VERSION 5.7 ;
BUSBITCHARS "[]" ;
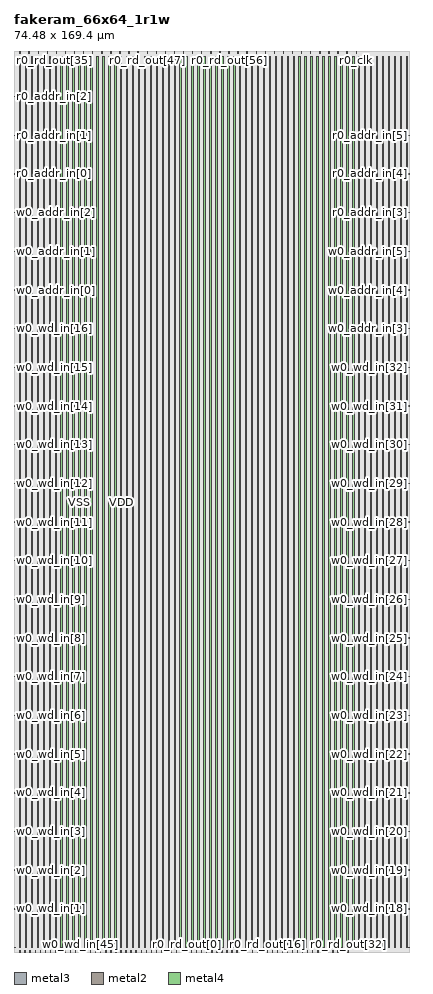
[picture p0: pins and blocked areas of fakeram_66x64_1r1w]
MACRO fakeram_66x64_1r1w
  FOREIGN fakeram_66x64_1r1w 0 0 ;
  SYMMETRY X Y R90 ;
  SIZE 74.480 BY 169.400 ;
  CLASS BLOCK ;
  PIN w0_wd_in[0]
    DIRECTION INPUT ;
    USE SIGNAL ;
    SHAPE ABUTMENT ;
    PORT
      LAYER metal3 ;
      RECT 0.000 0.805 0.210 0.875 ;
    END
  END w0_wd_in[0]
  PIN w0_wd_in[1]
    DIRECTION INPUT ;
    USE SIGNAL ;
    SHAPE ABUTMENT ;
    PORT
      LAYER metal3 ;
      RECT 0.000 8.085 0.210 8.155 ;
    END
  END w0_wd_in[1]
  PIN w0_wd_in[2]
    DIRECTION INPUT ;
    USE SIGNAL ;
    SHAPE ABUTMENT ;
    PORT
      LAYER metal3 ;
      RECT 0.000 15.365 0.210 15.435 ;
    END
  END w0_wd_in[2]
  PIN w0_wd_in[3]
    DIRECTION INPUT ;
    USE SIGNAL ;
    SHAPE ABUTMENT ;
    PORT
      LAYER metal3 ;
      RECT 0.000 22.645 0.210 22.715 ;
    END
  END w0_wd_in[3]
  PIN w0_wd_in[4]
    DIRECTION INPUT ;
    USE SIGNAL ;
    SHAPE ABUTMENT ;
    PORT
      LAYER metal3 ;
      RECT 0.000 29.925 0.210 29.995 ;
    END
  END w0_wd_in[4]
  PIN w0_wd_in[5]
    DIRECTION INPUT ;
    USE SIGNAL ;
    SHAPE ABUTMENT ;
    PORT
      LAYER metal3 ;
      RECT 0.000 37.205 0.210 37.275 ;
    END
  END w0_wd_in[5]
  PIN w0_wd_in[6]
    DIRECTION INPUT ;
    USE SIGNAL ;
    SHAPE ABUTMENT ;
    PORT
      LAYER metal3 ;
      RECT 0.000 44.485 0.210 44.555 ;
    END
  END w0_wd_in[6]
  PIN w0_wd_in[7]
    DIRECTION INPUT ;
    USE SIGNAL ;
    SHAPE ABUTMENT ;
    PORT
      LAYER metal3 ;
      RECT 0.000 51.765 0.210 51.835 ;
    END
  END w0_wd_in[7]
  PIN w0_wd_in[8]
    DIRECTION INPUT ;
    USE SIGNAL ;
    SHAPE ABUTMENT ;
    PORT
      LAYER metal3 ;
      RECT 0.000 59.045 0.210 59.115 ;
    END
  END w0_wd_in[8]
  PIN w0_wd_in[9]
    DIRECTION INPUT ;
    USE SIGNAL ;
    SHAPE ABUTMENT ;
    PORT
      LAYER metal3 ;
      RECT 0.000 66.325 0.210 66.395 ;
    END
  END w0_wd_in[9]
  PIN w0_wd_in[10]
    DIRECTION INPUT ;
    USE SIGNAL ;
    SHAPE ABUTMENT ;
    PORT
      LAYER metal3 ;
      RECT 0.000 73.605 0.210 73.675 ;
    END
  END w0_wd_in[10]
  PIN w0_wd_in[11]
    DIRECTION INPUT ;
    USE SIGNAL ;
    SHAPE ABUTMENT ;
    PORT
      LAYER metal3 ;
      RECT 0.000 80.885 0.210 80.955 ;
    END
  END w0_wd_in[11]
  PIN w0_wd_in[12]
    DIRECTION INPUT ;
    USE SIGNAL ;
    SHAPE ABUTMENT ;
    PORT
      LAYER metal3 ;
      RECT 0.000 88.165 0.210 88.235 ;
    END
  END w0_wd_in[12]
  PIN w0_wd_in[13]
    DIRECTION INPUT ;
    USE SIGNAL ;
    SHAPE ABUTMENT ;
    PORT
      LAYER metal3 ;
      RECT 0.000 95.445 0.210 95.515 ;
    END
  END w0_wd_in[13]
  PIN w0_wd_in[14]
    DIRECTION INPUT ;
    USE SIGNAL ;
    SHAPE ABUTMENT ;
    PORT
      LAYER metal3 ;
      RECT 0.000 102.725 0.210 102.795 ;
    END
  END w0_wd_in[14]
  PIN w0_wd_in[15]
    DIRECTION INPUT ;
    USE SIGNAL ;
    SHAPE ABUTMENT ;
    PORT
      LAYER metal3 ;
      RECT 0.000 110.005 0.210 110.075 ;
    END
  END w0_wd_in[15]
  PIN w0_wd_in[16]
    DIRECTION INPUT ;
    USE SIGNAL ;
    SHAPE ABUTMENT ;
    PORT
      LAYER metal3 ;
      RECT 0.000 117.285 0.210 117.355 ;
    END
  END w0_wd_in[16]
  PIN w0_wd_in[17]
    DIRECTION INPUT ;
    USE SIGNAL ;
    SHAPE ABUTMENT ;
    PORT
      LAYER metal3 ;
      RECT 74.270 0.805 74.480 0.875 ;
    END
  END w0_wd_in[17]
  PIN w0_wd_in[18]
    DIRECTION INPUT ;
    USE SIGNAL ;
    SHAPE ABUTMENT ;
    PORT
      LAYER metal3 ;
      RECT 74.270 8.085 74.480 8.155 ;
    END
  END w0_wd_in[18]
  PIN w0_wd_in[19]
    DIRECTION INPUT ;
    USE SIGNAL ;
    SHAPE ABUTMENT ;
    PORT
      LAYER metal3 ;
      RECT 74.270 15.365 74.480 15.435 ;
    END
  END w0_wd_in[19]
  PIN w0_wd_in[20]
    DIRECTION INPUT ;
    USE SIGNAL ;
    SHAPE ABUTMENT ;
    PORT
      LAYER metal3 ;
      RECT 74.270 22.645 74.480 22.715 ;
    END
  END w0_wd_in[20]
  PIN w0_wd_in[21]
    DIRECTION INPUT ;
    USE SIGNAL ;
    SHAPE ABUTMENT ;
    PORT
      LAYER metal3 ;
      RECT 74.270 29.925 74.480 29.995 ;
    END
  END w0_wd_in[21]
  PIN w0_wd_in[22]
    DIRECTION INPUT ;
    USE SIGNAL ;
    SHAPE ABUTMENT ;
    PORT
      LAYER metal3 ;
      RECT 74.270 37.205 74.480 37.275 ;
    END
  END w0_wd_in[22]
  PIN w0_wd_in[23]
    DIRECTION INPUT ;
    USE SIGNAL ;
    SHAPE ABUTMENT ;
    PORT
      LAYER metal3 ;
      RECT 74.270 44.485 74.480 44.555 ;
    END
  END w0_wd_in[23]
  PIN w0_wd_in[24]
    DIRECTION INPUT ;
    USE SIGNAL ;
    SHAPE ABUTMENT ;
    PORT
      LAYER metal3 ;
      RECT 74.270 51.765 74.480 51.835 ;
    END
  END w0_wd_in[24]
  PIN w0_wd_in[25]
    DIRECTION INPUT ;
    USE SIGNAL ;
    SHAPE ABUTMENT ;
    PORT
      LAYER metal3 ;
      RECT 74.270 59.045 74.480 59.115 ;
    END
  END w0_wd_in[25]
  PIN w0_wd_in[26]
    DIRECTION INPUT ;
    USE SIGNAL ;
    SHAPE ABUTMENT ;
    PORT
      LAYER metal3 ;
      RECT 74.270 66.325 74.480 66.395 ;
    END
  END w0_wd_in[26]
  PIN w0_wd_in[27]
    DIRECTION INPUT ;
    USE SIGNAL ;
    SHAPE ABUTMENT ;
    PORT
      LAYER metal3 ;
      RECT 74.270 73.605 74.480 73.675 ;
    END
  END w0_wd_in[27]
  PIN w0_wd_in[28]
    DIRECTION INPUT ;
    USE SIGNAL ;
    SHAPE ABUTMENT ;
    PORT
      LAYER metal3 ;
      RECT 74.270 80.885 74.480 80.955 ;
    END
  END w0_wd_in[28]
  PIN w0_wd_in[29]
    DIRECTION INPUT ;
    USE SIGNAL ;
    SHAPE ABUTMENT ;
    PORT
      LAYER metal3 ;
      RECT 74.270 88.165 74.480 88.235 ;
    END
  END w0_wd_in[29]
  PIN w0_wd_in[30]
    DIRECTION INPUT ;
    USE SIGNAL ;
    SHAPE ABUTMENT ;
    PORT
      LAYER metal3 ;
      RECT 74.270 95.445 74.480 95.515 ;
    END
  END w0_wd_in[30]
  PIN w0_wd_in[31]
    DIRECTION INPUT ;
    USE SIGNAL ;
    SHAPE ABUTMENT ;
    PORT
      LAYER metal3 ;
      RECT 74.270 102.725 74.480 102.795 ;
    END
  END w0_wd_in[31]
  PIN w0_wd_in[32]
    DIRECTION INPUT ;
    USE SIGNAL ;
    SHAPE ABUTMENT ;
    PORT
      LAYER metal3 ;
      RECT 74.270 110.005 74.480 110.075 ;
    END
  END w0_wd_in[32]
  PIN w0_wd_in[33]
    DIRECTION INPUT ;
    USE SIGNAL ;
    SHAPE ABUTMENT ;
    PORT
      LAYER metal2 ;
      RECT 1.105 0.000 1.175 0.210 ;
    END
  END w0_wd_in[33]
  PIN w0_wd_in[34]
    DIRECTION INPUT ;
    USE SIGNAL ;
    SHAPE ABUTMENT ;
    PORT
      LAYER metal2 ;
      RECT 2.055 0.000 2.125 0.210 ;
    END
  END w0_wd_in[34]
  PIN w0_wd_in[35]
    DIRECTION INPUT ;
    USE SIGNAL ;
    SHAPE ABUTMENT ;
    PORT
      LAYER metal2 ;
      RECT 3.005 0.000 3.075 0.210 ;
    END
  END w0_wd_in[35]
  PIN w0_wd_in[36]
    DIRECTION INPUT ;
    USE SIGNAL ;
    SHAPE ABUTMENT ;
    PORT
      LAYER metal2 ;
      RECT 3.955 0.000 4.025 0.210 ;
    END
  END w0_wd_in[36]
  PIN w0_wd_in[37]
    DIRECTION INPUT ;
    USE SIGNAL ;
    SHAPE ABUTMENT ;
    PORT
      LAYER metal2 ;
      RECT 4.905 0.000 4.975 0.210 ;
    END
  END w0_wd_in[37]
  PIN w0_wd_in[38]
    DIRECTION INPUT ;
    USE SIGNAL ;
    SHAPE ABUTMENT ;
    PORT
      LAYER metal2 ;
      RECT 5.855 0.000 5.925 0.210 ;
    END
  END w0_wd_in[38]
  PIN w0_wd_in[39]
    DIRECTION INPUT ;
    USE SIGNAL ;
    SHAPE ABUTMENT ;
    PORT
      LAYER metal2 ;
      RECT 6.805 0.000 6.875 0.210 ;
    END
  END w0_wd_in[39]
  PIN w0_wd_in[40]
    DIRECTION INPUT ;
    USE SIGNAL ;
    SHAPE ABUTMENT ;
    PORT
      LAYER metal2 ;
      RECT 7.755 0.000 7.825 0.210 ;
    END
  END w0_wd_in[40]
  PIN w0_wd_in[41]
    DIRECTION INPUT ;
    USE SIGNAL ;
    SHAPE ABUTMENT ;
    PORT
      LAYER metal2 ;
      RECT 8.705 0.000 8.775 0.210 ;
    END
  END w0_wd_in[41]
  PIN w0_wd_in[42]
    DIRECTION INPUT ;
    USE SIGNAL ;
    SHAPE ABUTMENT ;
    PORT
      LAYER metal2 ;
      RECT 9.655 0.000 9.725 0.210 ;
    END
  END w0_wd_in[42]
  PIN w0_wd_in[43]
    DIRECTION INPUT ;
    USE SIGNAL ;
    SHAPE ABUTMENT ;
    PORT
      LAYER metal2 ;
      RECT 10.605 0.000 10.675 0.210 ;
    END
  END w0_wd_in[43]
  PIN w0_wd_in[44]
    DIRECTION INPUT ;
    USE SIGNAL ;
    SHAPE ABUTMENT ;
    PORT
      LAYER metal2 ;
      RECT 11.555 0.000 11.625 0.210 ;
    END
  END w0_wd_in[44]
  PIN w0_wd_in[45]
    DIRECTION INPUT ;
    USE SIGNAL ;
    SHAPE ABUTMENT ;
    PORT
      LAYER metal2 ;
      RECT 12.505 0.000 12.575 0.210 ;
    END
  END w0_wd_in[45]
  PIN w0_wd_in[46]
    DIRECTION INPUT ;
    USE SIGNAL ;
    SHAPE ABUTMENT ;
    PORT
      LAYER metal2 ;
      RECT 13.455 0.000 13.525 0.210 ;
    END
  END w0_wd_in[46]
  PIN w0_wd_in[47]
    DIRECTION INPUT ;
    USE SIGNAL ;
    SHAPE ABUTMENT ;
    PORT
      LAYER metal2 ;
      RECT 14.405 0.000 14.475 0.210 ;
    END
  END w0_wd_in[47]
  PIN w0_wd_in[48]
    DIRECTION INPUT ;
    USE SIGNAL ;
    SHAPE ABUTMENT ;
    PORT
      LAYER metal2 ;
      RECT 15.355 0.000 15.425 0.210 ;
    END
  END w0_wd_in[48]
  PIN w0_wd_in[49]
    DIRECTION INPUT ;
    USE SIGNAL ;
    SHAPE ABUTMENT ;
    PORT
      LAYER metal2 ;
      RECT 16.305 0.000 16.375 0.210 ;
    END
  END w0_wd_in[49]
  PIN w0_wd_in[50]
    DIRECTION INPUT ;
    USE SIGNAL ;
    SHAPE ABUTMENT ;
    PORT
      LAYER metal2 ;
      RECT 17.255 0.000 17.325 0.210 ;
    END
  END w0_wd_in[50]
  PIN w0_wd_in[51]
    DIRECTION INPUT ;
    USE SIGNAL ;
    SHAPE ABUTMENT ;
    PORT
      LAYER metal2 ;
      RECT 18.205 0.000 18.275 0.210 ;
    END
  END w0_wd_in[51]
  PIN w0_wd_in[52]
    DIRECTION INPUT ;
    USE SIGNAL ;
    SHAPE ABUTMENT ;
    PORT
      LAYER metal2 ;
      RECT 19.155 0.000 19.225 0.210 ;
    END
  END w0_wd_in[52]
  PIN w0_wd_in[53]
    DIRECTION INPUT ;
    USE SIGNAL ;
    SHAPE ABUTMENT ;
    PORT
      LAYER metal2 ;
      RECT 20.105 0.000 20.175 0.210 ;
    END
  END w0_wd_in[53]
  PIN w0_wd_in[54]
    DIRECTION INPUT ;
    USE SIGNAL ;
    SHAPE ABUTMENT ;
    PORT
      LAYER metal2 ;
      RECT 21.055 0.000 21.125 0.210 ;
    END
  END w0_wd_in[54]
  PIN w0_wd_in[55]
    DIRECTION INPUT ;
    USE SIGNAL ;
    SHAPE ABUTMENT ;
    PORT
      LAYER metal2 ;
      RECT 22.005 0.000 22.075 0.210 ;
    END
  END w0_wd_in[55]
  PIN w0_wd_in[56]
    DIRECTION INPUT ;
    USE SIGNAL ;
    SHAPE ABUTMENT ;
    PORT
      LAYER metal2 ;
      RECT 22.955 0.000 23.025 0.210 ;
    END
  END w0_wd_in[56]
  PIN w0_wd_in[57]
    DIRECTION INPUT ;
    USE SIGNAL ;
    SHAPE ABUTMENT ;
    PORT
      LAYER metal2 ;
      RECT 23.905 0.000 23.975 0.210 ;
    END
  END w0_wd_in[57]
  PIN w0_wd_in[58]
    DIRECTION INPUT ;
    USE SIGNAL ;
    SHAPE ABUTMENT ;
    PORT
      LAYER metal2 ;
      RECT 24.855 0.000 24.925 0.210 ;
    END
  END w0_wd_in[58]
  PIN w0_wd_in[59]
    DIRECTION INPUT ;
    USE SIGNAL ;
    SHAPE ABUTMENT ;
    PORT
      LAYER metal2 ;
      RECT 25.805 0.000 25.875 0.210 ;
    END
  END w0_wd_in[59]
  PIN w0_wd_in[60]
    DIRECTION INPUT ;
    USE SIGNAL ;
    SHAPE ABUTMENT ;
    PORT
      LAYER metal2 ;
      RECT 26.755 0.000 26.825 0.210 ;
    END
  END w0_wd_in[60]
  PIN w0_wd_in[61]
    DIRECTION INPUT ;
    USE SIGNAL ;
    SHAPE ABUTMENT ;
    PORT
      LAYER metal2 ;
      RECT 27.705 0.000 27.775 0.210 ;
    END
  END w0_wd_in[61]
  PIN w0_wd_in[62]
    DIRECTION INPUT ;
    USE SIGNAL ;
    SHAPE ABUTMENT ;
    PORT
      LAYER metal2 ;
      RECT 28.655 0.000 28.725 0.210 ;
    END
  END w0_wd_in[62]
  PIN w0_wd_in[63]
    DIRECTION INPUT ;
    USE SIGNAL ;
    SHAPE ABUTMENT ;
    PORT
      LAYER metal2 ;
      RECT 29.605 0.000 29.675 0.210 ;
    END
  END w0_wd_in[63]
  PIN w0_wd_in[64]
    DIRECTION INPUT ;
    USE SIGNAL ;
    SHAPE ABUTMENT ;
    PORT
      LAYER metal2 ;
      RECT 30.555 0.000 30.625 0.210 ;
    END
  END w0_wd_in[64]
  PIN w0_wd_in[65]
    DIRECTION INPUT ;
    USE SIGNAL ;
    SHAPE ABUTMENT ;
    PORT
      LAYER metal2 ;
      RECT 31.505 0.000 31.575 0.210 ;
    END
  END w0_wd_in[65]
  PIN r0_rd_out[0]
    DIRECTION OUTPUT ;
    USE SIGNAL ;
    SHAPE ABUTMENT ;
    PORT
      LAYER metal2 ;
      RECT 32.455 0.000 32.525 0.210 ;
    END
  END r0_rd_out[0]
  PIN r0_rd_out[1]
    DIRECTION OUTPUT ;
    USE SIGNAL ;
    SHAPE ABUTMENT ;
    PORT
      LAYER metal2 ;
      RECT 33.405 0.000 33.475 0.210 ;
    END
  END r0_rd_out[1]
  PIN r0_rd_out[2]
    DIRECTION OUTPUT ;
    USE SIGNAL ;
    SHAPE ABUTMENT ;
    PORT
      LAYER metal2 ;
      RECT 34.355 0.000 34.425 0.210 ;
    END
  END r0_rd_out[2]
  PIN r0_rd_out[3]
    DIRECTION OUTPUT ;
    USE SIGNAL ;
    SHAPE ABUTMENT ;
    PORT
      LAYER metal2 ;
      RECT 35.305 0.000 35.375 0.210 ;
    END
  END r0_rd_out[3]
  PIN r0_rd_out[4]
    DIRECTION OUTPUT ;
    USE SIGNAL ;
    SHAPE ABUTMENT ;
    PORT
      LAYER metal2 ;
      RECT 36.255 0.000 36.325 0.210 ;
    END
  END r0_rd_out[4]
  PIN r0_rd_out[5]
    DIRECTION OUTPUT ;
    USE SIGNAL ;
    SHAPE ABUTMENT ;
    PORT
      LAYER metal2 ;
      RECT 37.205 0.000 37.275 0.210 ;
    END
  END r0_rd_out[5]
  PIN r0_rd_out[6]
    DIRECTION OUTPUT ;
    USE SIGNAL ;
    SHAPE ABUTMENT ;
    PORT
      LAYER metal2 ;
      RECT 38.155 0.000 38.225 0.210 ;
    END
  END r0_rd_out[6]
  PIN r0_rd_out[7]
    DIRECTION OUTPUT ;
    USE SIGNAL ;
    SHAPE ABUTMENT ;
    PORT
      LAYER metal2 ;
      RECT 39.105 0.000 39.175 0.210 ;
    END
  END r0_rd_out[7]
  PIN r0_rd_out[8]
    DIRECTION OUTPUT ;
    USE SIGNAL ;
    SHAPE ABUTMENT ;
    PORT
      LAYER metal2 ;
      RECT 40.055 0.000 40.125 0.210 ;
    END
  END r0_rd_out[8]
  PIN r0_rd_out[9]
    DIRECTION OUTPUT ;
    USE SIGNAL ;
    SHAPE ABUTMENT ;
    PORT
      LAYER metal2 ;
      RECT 41.005 0.000 41.075 0.210 ;
    END
  END r0_rd_out[9]
  PIN r0_rd_out[10]
    DIRECTION OUTPUT ;
    USE SIGNAL ;
    SHAPE ABUTMENT ;
    PORT
      LAYER metal2 ;
      RECT 41.955 0.000 42.025 0.210 ;
    END
  END r0_rd_out[10]
  PIN r0_rd_out[11]
    DIRECTION OUTPUT ;
    USE SIGNAL ;
    SHAPE ABUTMENT ;
    PORT
      LAYER metal2 ;
      RECT 42.905 0.000 42.975 0.210 ;
    END
  END r0_rd_out[11]
  PIN r0_rd_out[12]
    DIRECTION OUTPUT ;
    USE SIGNAL ;
    SHAPE ABUTMENT ;
    PORT
      LAYER metal2 ;
      RECT 43.855 0.000 43.925 0.210 ;
    END
  END r0_rd_out[12]
  PIN r0_rd_out[13]
    DIRECTION OUTPUT ;
    USE SIGNAL ;
    SHAPE ABUTMENT ;
    PORT
      LAYER metal2 ;
      RECT 44.805 0.000 44.875 0.210 ;
    END
  END r0_rd_out[13]
  PIN r0_rd_out[14]
    DIRECTION OUTPUT ;
    USE SIGNAL ;
    SHAPE ABUTMENT ;
    PORT
      LAYER metal2 ;
      RECT 45.755 0.000 45.825 0.210 ;
    END
  END r0_rd_out[14]
  PIN r0_rd_out[15]
    DIRECTION OUTPUT ;
    USE SIGNAL ;
    SHAPE ABUTMENT ;
    PORT
      LAYER metal2 ;
      RECT 46.705 0.000 46.775 0.210 ;
    END
  END r0_rd_out[15]
  PIN r0_rd_out[16]
    DIRECTION OUTPUT ;
    USE SIGNAL ;
    SHAPE ABUTMENT ;
    PORT
      LAYER metal2 ;
      RECT 47.655 0.000 47.725 0.210 ;
    END
  END r0_rd_out[16]
  PIN r0_rd_out[17]
    DIRECTION OUTPUT ;
    USE SIGNAL ;
    SHAPE ABUTMENT ;
    PORT
      LAYER metal2 ;
      RECT 48.605 0.000 48.675 0.210 ;
    END
  END r0_rd_out[17]
  PIN r0_rd_out[18]
    DIRECTION OUTPUT ;
    USE SIGNAL ;
    SHAPE ABUTMENT ;
    PORT
      LAYER metal2 ;
      RECT 49.555 0.000 49.625 0.210 ;
    END
  END r0_rd_out[18]
  PIN r0_rd_out[19]
    DIRECTION OUTPUT ;
    USE SIGNAL ;
    SHAPE ABUTMENT ;
    PORT
      LAYER metal2 ;
      RECT 50.505 0.000 50.575 0.210 ;
    END
  END r0_rd_out[19]
  PIN r0_rd_out[20]
    DIRECTION OUTPUT ;
    USE SIGNAL ;
    SHAPE ABUTMENT ;
    PORT
      LAYER metal2 ;
      RECT 51.455 0.000 51.525 0.210 ;
    END
  END r0_rd_out[20]
  PIN r0_rd_out[21]
    DIRECTION OUTPUT ;
    USE SIGNAL ;
    SHAPE ABUTMENT ;
    PORT
      LAYER metal2 ;
      RECT 52.405 0.000 52.475 0.210 ;
    END
  END r0_rd_out[21]
  PIN r0_rd_out[22]
    DIRECTION OUTPUT ;
    USE SIGNAL ;
    SHAPE ABUTMENT ;
    PORT
      LAYER metal2 ;
      RECT 53.355 0.000 53.425 0.210 ;
    END
  END r0_rd_out[22]
  PIN r0_rd_out[23]
    DIRECTION OUTPUT ;
    USE SIGNAL ;
    SHAPE ABUTMENT ;
    PORT
      LAYER metal2 ;
      RECT 54.305 0.000 54.375 0.210 ;
    END
  END r0_rd_out[23]
  PIN r0_rd_out[24]
    DIRECTION OUTPUT ;
    USE SIGNAL ;
    SHAPE ABUTMENT ;
    PORT
      LAYER metal2 ;
      RECT 55.255 0.000 55.325 0.210 ;
    END
  END r0_rd_out[24]
  PIN r0_rd_out[25]
    DIRECTION OUTPUT ;
    USE SIGNAL ;
    SHAPE ABUTMENT ;
    PORT
      LAYER metal2 ;
      RECT 56.205 0.000 56.275 0.210 ;
    END
  END r0_rd_out[25]
  PIN r0_rd_out[26]
    DIRECTION OUTPUT ;
    USE SIGNAL ;
    SHAPE ABUTMENT ;
    PORT
      LAYER metal2 ;
      RECT 57.155 0.000 57.225 0.210 ;
    END
  END r0_rd_out[26]
  PIN r0_rd_out[27]
    DIRECTION OUTPUT ;
    USE SIGNAL ;
    SHAPE ABUTMENT ;
    PORT
      LAYER metal2 ;
      RECT 58.105 0.000 58.175 0.210 ;
    END
  END r0_rd_out[27]
  PIN r0_rd_out[28]
    DIRECTION OUTPUT ;
    USE SIGNAL ;
    SHAPE ABUTMENT ;
    PORT
      LAYER metal2 ;
      RECT 59.055 0.000 59.125 0.210 ;
    END
  END r0_rd_out[28]
  PIN r0_rd_out[29]
    DIRECTION OUTPUT ;
    USE SIGNAL ;
    SHAPE ABUTMENT ;
    PORT
      LAYER metal2 ;
      RECT 60.005 0.000 60.075 0.210 ;
    END
  END r0_rd_out[29]
  PIN r0_rd_out[30]
    DIRECTION OUTPUT ;
    USE SIGNAL ;
    SHAPE ABUTMENT ;
    PORT
      LAYER metal2 ;
      RECT 60.955 0.000 61.025 0.210 ;
    END
  END r0_rd_out[30]
  PIN r0_rd_out[31]
    DIRECTION OUTPUT ;
    USE SIGNAL ;
    SHAPE ABUTMENT ;
    PORT
      LAYER metal2 ;
      RECT 61.905 0.000 61.975 0.210 ;
    END
  END r0_rd_out[31]
  PIN r0_rd_out[32]
    DIRECTION OUTPUT ;
    USE SIGNAL ;
    SHAPE ABUTMENT ;
    PORT
      LAYER metal2 ;
      RECT 62.855 0.000 62.925 0.210 ;
    END
  END r0_rd_out[32]
  PIN r0_rd_out[33]
    DIRECTION OUTPUT ;
    USE SIGNAL ;
    SHAPE ABUTMENT ;
    PORT
      LAYER metal2 ;
      RECT 1.105 169.190 1.175 169.400 ;
    END
  END r0_rd_out[33]
  PIN r0_rd_out[34]
    DIRECTION OUTPUT ;
    USE SIGNAL ;
    SHAPE ABUTMENT ;
    PORT
      LAYER metal2 ;
      RECT 2.815 169.190 2.885 169.400 ;
    END
  END r0_rd_out[34]
  PIN r0_rd_out[35]
    DIRECTION OUTPUT ;
    USE SIGNAL ;
    SHAPE ABUTMENT ;
    PORT
      LAYER metal2 ;
      RECT 4.525 169.190 4.595 169.400 ;
    END
  END r0_rd_out[35]
  PIN r0_rd_out[36]
    DIRECTION OUTPUT ;
    USE SIGNAL ;
    SHAPE ABUTMENT ;
    PORT
      LAYER metal2 ;
      RECT 6.235 169.190 6.305 169.400 ;
    END
  END r0_rd_out[36]
  PIN r0_rd_out[37]
    DIRECTION OUTPUT ;
    USE SIGNAL ;
    SHAPE ABUTMENT ;
    PORT
      LAYER metal2 ;
      RECT 7.945 169.190 8.015 169.400 ;
    END
  END r0_rd_out[37]
  PIN r0_rd_out[38]
    DIRECTION OUTPUT ;
    USE SIGNAL ;
    SHAPE ABUTMENT ;
    PORT
      LAYER metal2 ;
      RECT 9.655 169.190 9.725 169.400 ;
    END
  END r0_rd_out[38]
  PIN r0_rd_out[39]
    DIRECTION OUTPUT ;
    USE SIGNAL ;
    SHAPE ABUTMENT ;
    PORT
      LAYER metal2 ;
      RECT 11.365 169.190 11.435 169.400 ;
    END
  END r0_rd_out[39]
  PIN r0_rd_out[40]
    DIRECTION OUTPUT ;
    USE SIGNAL ;
    SHAPE ABUTMENT ;
    PORT
      LAYER metal2 ;
      RECT 13.075 169.190 13.145 169.400 ;
    END
  END r0_rd_out[40]
  PIN r0_rd_out[41]
    DIRECTION OUTPUT ;
    USE SIGNAL ;
    SHAPE ABUTMENT ;
    PORT
      LAYER metal2 ;
      RECT 14.785 169.190 14.855 169.400 ;
    END
  END r0_rd_out[41]
  PIN r0_rd_out[42]
    DIRECTION OUTPUT ;
    USE SIGNAL ;
    SHAPE ABUTMENT ;
    PORT
      LAYER metal2 ;
      RECT 16.495 169.190 16.565 169.400 ;
    END
  END r0_rd_out[42]
  PIN r0_rd_out[43]
    DIRECTION OUTPUT ;
    USE SIGNAL ;
    SHAPE ABUTMENT ;
    PORT
      LAYER metal2 ;
      RECT 18.205 169.190 18.275 169.400 ;
    END
  END r0_rd_out[43]
  PIN r0_rd_out[44]
    DIRECTION OUTPUT ;
    USE SIGNAL ;
    SHAPE ABUTMENT ;
    PORT
      LAYER metal2 ;
      RECT 19.915 169.190 19.985 169.400 ;
    END
  END r0_rd_out[44]
  PIN r0_rd_out[45]
    DIRECTION OUTPUT ;
    USE SIGNAL ;
    SHAPE ABUTMENT ;
    PORT
      LAYER metal2 ;
      RECT 21.625 169.190 21.695 169.400 ;
    END
  END r0_rd_out[45]
  PIN r0_rd_out[46]
    DIRECTION OUTPUT ;
    USE SIGNAL ;
    SHAPE ABUTMENT ;
    PORT
      LAYER metal2 ;
      RECT 23.335 169.190 23.405 169.400 ;
    END
  END r0_rd_out[46]
  PIN r0_rd_out[47]
    DIRECTION OUTPUT ;
    USE SIGNAL ;
    SHAPE ABUTMENT ;
    PORT
      LAYER metal2 ;
      RECT 25.045 169.190 25.115 169.400 ;
    END
  END r0_rd_out[47]
  PIN r0_rd_out[48]
    DIRECTION OUTPUT ;
    USE SIGNAL ;
    SHAPE ABUTMENT ;
    PORT
      LAYER metal2 ;
      RECT 26.755 169.190 26.825 169.400 ;
    END
  END r0_rd_out[48]
  PIN r0_rd_out[49]
    DIRECTION OUTPUT ;
    USE SIGNAL ;
    SHAPE ABUTMENT ;
    PORT
      LAYER metal2 ;
      RECT 28.465 169.190 28.535 169.400 ;
    END
  END r0_rd_out[49]
  PIN r0_rd_out[50]
    DIRECTION OUTPUT ;
    USE SIGNAL ;
    SHAPE ABUTMENT ;
    PORT
      LAYER metal2 ;
      RECT 30.175 169.190 30.245 169.400 ;
    END
  END r0_rd_out[50]
  PIN r0_rd_out[51]
    DIRECTION OUTPUT ;
    USE SIGNAL ;
    SHAPE ABUTMENT ;
    PORT
      LAYER metal2 ;
      RECT 31.885 169.190 31.955 169.400 ;
    END
  END r0_rd_out[51]
  PIN r0_rd_out[52]
    DIRECTION OUTPUT ;
    USE SIGNAL ;
    SHAPE ABUTMENT ;
    PORT
      LAYER metal2 ;
      RECT 33.595 169.190 33.665 169.400 ;
    END
  END r0_rd_out[52]
  PIN r0_rd_out[53]
    DIRECTION OUTPUT ;
    USE SIGNAL ;
    SHAPE ABUTMENT ;
    PORT
      LAYER metal2 ;
      RECT 35.305 169.190 35.375 169.400 ;
    END
  END r0_rd_out[53]
  PIN r0_rd_out[54]
    DIRECTION OUTPUT ;
    USE SIGNAL ;
    SHAPE ABUTMENT ;
    PORT
      LAYER metal2 ;
      RECT 37.015 169.190 37.085 169.400 ;
    END
  END r0_rd_out[54]
  PIN r0_rd_out[55]
    DIRECTION OUTPUT ;
    USE SIGNAL ;
    SHAPE ABUTMENT ;
    PORT
      LAYER metal2 ;
      RECT 38.725 169.190 38.795 169.400 ;
    END
  END r0_rd_out[55]
  PIN r0_rd_out[56]
    DIRECTION OUTPUT ;
    USE SIGNAL ;
    SHAPE ABUTMENT ;
    PORT
      LAYER metal2 ;
      RECT 40.435 169.190 40.505 169.400 ;
    END
  END r0_rd_out[56]
  PIN r0_rd_out[57]
    DIRECTION OUTPUT ;
    USE SIGNAL ;
    SHAPE ABUTMENT ;
    PORT
      LAYER metal2 ;
      RECT 42.145 169.190 42.215 169.400 ;
    END
  END r0_rd_out[57]
  PIN r0_rd_out[58]
    DIRECTION OUTPUT ;
    USE SIGNAL ;
    SHAPE ABUTMENT ;
    PORT
      LAYER metal2 ;
      RECT 43.855 169.190 43.925 169.400 ;
    END
  END r0_rd_out[58]
  PIN r0_rd_out[59]
    DIRECTION OUTPUT ;
    USE SIGNAL ;
    SHAPE ABUTMENT ;
    PORT
      LAYER metal2 ;
      RECT 45.565 169.190 45.635 169.400 ;
    END
  END r0_rd_out[59]
  PIN r0_rd_out[60]
    DIRECTION OUTPUT ;
    USE SIGNAL ;
    SHAPE ABUTMENT ;
    PORT
      LAYER metal2 ;
      RECT 47.275 169.190 47.345 169.400 ;
    END
  END r0_rd_out[60]
  PIN r0_rd_out[61]
    DIRECTION OUTPUT ;
    USE SIGNAL ;
    SHAPE ABUTMENT ;
    PORT
      LAYER metal2 ;
      RECT 48.985 169.190 49.055 169.400 ;
    END
  END r0_rd_out[61]
  PIN r0_rd_out[62]
    DIRECTION OUTPUT ;
    USE SIGNAL ;
    SHAPE ABUTMENT ;
    PORT
      LAYER metal2 ;
      RECT 50.695 169.190 50.765 169.400 ;
    END
  END r0_rd_out[62]
  PIN r0_rd_out[63]
    DIRECTION OUTPUT ;
    USE SIGNAL ;
    SHAPE ABUTMENT ;
    PORT
      LAYER metal2 ;
      RECT 52.405 169.190 52.475 169.400 ;
    END
  END r0_rd_out[63]
  PIN r0_rd_out[64]
    DIRECTION OUTPUT ;
    USE SIGNAL ;
    SHAPE ABUTMENT ;
    PORT
      LAYER metal2 ;
      RECT 54.115 169.190 54.185 169.400 ;
    END
  END r0_rd_out[64]
  PIN r0_rd_out[65]
    DIRECTION OUTPUT ;
    USE SIGNAL ;
    SHAPE ABUTMENT ;
    PORT
      LAYER metal2 ;
      RECT 55.825 169.190 55.895 169.400 ;
    END
  END r0_rd_out[65]
  PIN w0_addr_in[0]
    DIRECTION INPUT ;
    USE SIGNAL ;
    SHAPE ABUTMENT ;
    PORT
      LAYER metal3 ;
      RECT 0.000 124.565 0.210 124.635 ;
    END
  END w0_addr_in[0]
  PIN w0_addr_in[1]
    DIRECTION INPUT ;
    USE SIGNAL ;
    SHAPE ABUTMENT ;
    PORT
      LAYER metal3 ;
      RECT 0.000 131.845 0.210 131.915 ;
    END
  END w0_addr_in[1]
  PIN w0_addr_in[2]
    DIRECTION INPUT ;
    USE SIGNAL ;
    SHAPE ABUTMENT ;
    PORT
      LAYER metal3 ;
      RECT 0.000 139.125 0.210 139.195 ;
    END
  END w0_addr_in[2]
  PIN w0_addr_in[3]
    DIRECTION INPUT ;
    USE SIGNAL ;
    SHAPE ABUTMENT ;
    PORT
      LAYER metal3 ;
      RECT 74.270 117.285 74.480 117.355 ;
    END
  END w0_addr_in[3]
  PIN w0_addr_in[4]
    DIRECTION INPUT ;
    USE SIGNAL ;
    SHAPE ABUTMENT ;
    PORT
      LAYER metal3 ;
      RECT 74.270 124.565 74.480 124.635 ;
    END
  END w0_addr_in[4]
  PIN w0_addr_in[5]
    DIRECTION INPUT ;
    USE SIGNAL ;
    SHAPE ABUTMENT ;
    PORT
      LAYER metal3 ;
      RECT 74.270 131.845 74.480 131.915 ;
    END
  END w0_addr_in[5]
  PIN r0_addr_in[0]
    DIRECTION INPUT ;
    USE SIGNAL ;
    SHAPE ABUTMENT ;
    PORT
      LAYER metal3 ;
      RECT 0.000 146.405 0.210 146.475 ;
    END
  END r0_addr_in[0]
  PIN r0_addr_in[1]
    DIRECTION INPUT ;
    USE SIGNAL ;
    SHAPE ABUTMENT ;
    PORT
      LAYER metal3 ;
      RECT 0.000 153.685 0.210 153.755 ;
    END
  END r0_addr_in[1]
  PIN r0_addr_in[2]
    DIRECTION INPUT ;
    USE SIGNAL ;
    SHAPE ABUTMENT ;
    PORT
      LAYER metal3 ;
      RECT 0.000 160.965 0.210 161.035 ;
    END
  END r0_addr_in[2]
  PIN r0_addr_in[3]
    DIRECTION INPUT ;
    USE SIGNAL ;
    SHAPE ABUTMENT ;
    PORT
      LAYER metal3 ;
      RECT 74.270 139.125 74.480 139.195 ;
    END
  END r0_addr_in[3]
  PIN r0_addr_in[4]
    DIRECTION INPUT ;
    USE SIGNAL ;
    SHAPE ABUTMENT ;
    PORT
      LAYER metal3 ;
      RECT 74.270 146.405 74.480 146.475 ;
    END
  END r0_addr_in[4]
  PIN r0_addr_in[5]
    DIRECTION INPUT ;
    USE SIGNAL ;
    SHAPE ABUTMENT ;
    PORT
      LAYER metal3 ;
      RECT 74.270 153.685 74.480 153.755 ;
    END
  END r0_addr_in[5]
  PIN w0_we_in
    DIRECTION INPUT ;
    USE SIGNAL ;
    SHAPE ABUTMENT ;
    PORT
      LAYER metal2 ;
      RECT 57.535 169.190 57.605 169.400 ;
    END
  END w0_we_in
  PIN w0_ce_in
    DIRECTION INPUT ;
    USE SIGNAL ;
    SHAPE ABUTMENT ;
    PORT
      LAYER metal2 ;
      RECT 59.245 169.190 59.315 169.400 ;
    END
  END w0_ce_in
  PIN w0_clk
    DIRECTION INPUT ;
    USE SIGNAL ;
    SHAPE ABUTMENT ;
    PORT
      LAYER metal2 ;
      RECT 60.955 169.190 61.025 169.400 ;
    END
  END w0_clk
  PIN r0_ce_in
    DIRECTION INPUT ;
    USE SIGNAL ;
    SHAPE ABUTMENT ;
    PORT
      LAYER metal2 ;
      RECT 62.665 169.190 62.735 169.400 ;
    END
  END r0_ce_in
  PIN r0_clk
    DIRECTION INPUT ;
    USE SIGNAL ;
    SHAPE ABUTMENT ;
    PORT
      LAYER metal2 ;
      RECT 64.375 169.190 64.445 169.400 ;
    END
  END r0_clk
  PIN VSS
    DIRECTION INOUT ;
    USE GROUND ;
    PORT
      LAYER metal4 ;
      RECT 1.000 0.840 1.280 168.560 ;
      RECT 3.240 0.840 3.520 168.560 ;
      RECT 5.480 0.840 5.760 168.560 ;
      RECT 7.720 0.840 8.000 168.560 ;
      RECT 9.960 0.840 10.240 168.560 ;
      RECT 12.200 0.840 12.480 168.560 ;
      RECT 14.440 0.840 14.720 168.560 ;
      RECT 16.680 0.840 16.960 168.560 ;
      RECT 18.920 0.840 19.200 168.560 ;
      RECT 21.160 0.840 21.440 168.560 ;
      RECT 23.400 0.840 23.680 168.560 ;
      RECT 25.640 0.840 25.920 168.560 ;
      RECT 27.880 0.840 28.160 168.560 ;
      RECT 30.120 0.840 30.400 168.560 ;
      RECT 32.360 0.840 32.640 168.560 ;
      RECT 34.600 0.840 34.880 168.560 ;
      RECT 36.840 0.840 37.120 168.560 ;
      RECT 39.080 0.840 39.360 168.560 ;
      RECT 41.320 0.840 41.600 168.560 ;
      RECT 43.560 0.840 43.840 168.560 ;
      RECT 45.800 0.840 46.080 168.560 ;
      RECT 48.040 0.840 48.320 168.560 ;
      RECT 50.280 0.840 50.560 168.560 ;
      RECT 52.520 0.840 52.800 168.560 ;
      RECT 54.760 0.840 55.040 168.560 ;
      RECT 57.000 0.840 57.280 168.560 ;
      RECT 59.240 0.840 59.520 168.560 ;
      RECT 61.480 0.840 61.760 168.560 ;
      RECT 63.720 0.840 64.000 168.560 ;
      RECT 65.960 0.840 66.240 168.560 ;
      RECT 68.200 0.840 68.480 168.560 ;
      RECT 70.440 0.840 70.720 168.560 ;
      RECT 72.680 0.840 72.960 168.560 ;
    END
  END VSS
  PIN VDD
    DIRECTION INOUT ;
    USE POWER ;
    PORT
      LAYER metal4 ;
      RECT 2.120 0.840 2.400 168.560 ;
      RECT 4.360 0.840 4.640 168.560 ;
      RECT 6.600 0.840 6.880 168.560 ;
      RECT 8.840 0.840 9.120 168.560 ;
      RECT 11.080 0.840 11.360 168.560 ;
      RECT 13.320 0.840 13.600 168.560 ;
      RECT 15.560 0.840 15.840 168.560 ;
      RECT 17.800 0.840 18.080 168.560 ;
      RECT 20.040 0.840 20.320 168.560 ;
      RECT 22.280 0.840 22.560 168.560 ;
      RECT 24.520 0.840 24.800 168.560 ;
      RECT 26.760 0.840 27.040 168.560 ;
      RECT 29.000 0.840 29.280 168.560 ;
      RECT 31.240 0.840 31.520 168.560 ;
      RECT 33.480 0.840 33.760 168.560 ;
      RECT 35.720 0.840 36.000 168.560 ;
      RECT 37.960 0.840 38.240 168.560 ;
      RECT 40.200 0.840 40.480 168.560 ;
      RECT 42.440 0.840 42.720 168.560 ;
      RECT 44.680 0.840 44.960 168.560 ;
      RECT 46.920 0.840 47.200 168.560 ;
      RECT 49.160 0.840 49.440 168.560 ;
      RECT 51.400 0.840 51.680 168.560 ;
      RECT 53.640 0.840 53.920 168.560 ;
      RECT 55.880 0.840 56.160 168.560 ;
      RECT 58.120 0.840 58.400 168.560 ;
      RECT 60.360 0.840 60.640 168.560 ;
      RECT 62.600 0.840 62.880 168.560 ;
      RECT 64.840 0.840 65.120 168.560 ;
      RECT 67.080 0.840 67.360 168.560 ;
      RECT 69.320 0.840 69.600 168.560 ;
      RECT 71.560 0.840 71.840 168.560 ;
      RECT 73.800 0.840 74.080 168.560 ;
    END
  END VDD
  OBS
    LAYER metal1 ;
    RECT 0 0 74.480 169.400 ;
    LAYER metal2 ;
    RECT 0 0 74.480 169.400 ;
    LAYER metal3 ;
    RECT 0 0 74.480 169.400 ;
    LAYER metal4 ;
    RECT 0 0 74.480 169.400 ;
    LAYER OVERLAP ;
    RECT 0 0 74.480 169.400 ;
  END
END fakeram_66x64_1r1w

END LIBRARY
